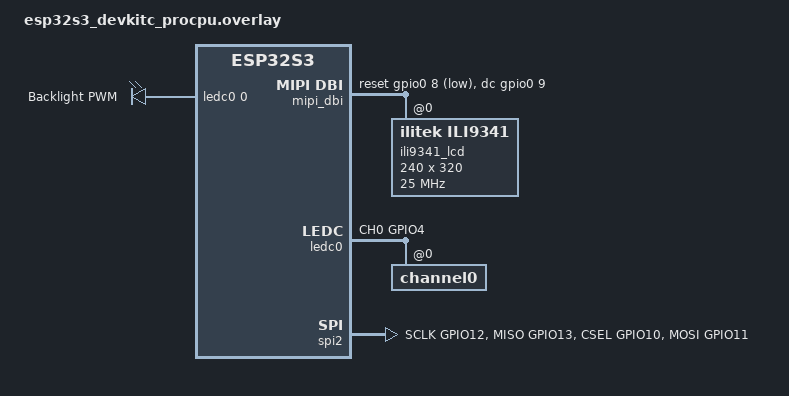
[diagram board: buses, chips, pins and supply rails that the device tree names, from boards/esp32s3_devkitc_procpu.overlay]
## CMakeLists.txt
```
cmake_minimum_required(VERSION 3.20.0)

set(CODECHECKER_ANALYZE_OPTS
    "--config;${CMAKE_SOURCE_DIR}/codechecker/codechecker.yml;"
    "--skip;${CMAKE_SOURCE_DIR}/codechecker/skip.codechecker"
    CACHE STRING "Code checker options")

# Find and load the Zephyr build system package
find_package(Zephyr REQUIRED HINTS $ENV{ZEPHYR_BASE})

# Define your project name
project(open_tempo)

# Target the application source code files
target_sources(app PRIVATE
    src/main.cpp
    src/GuiClock.cpp
    src/Threads.cpp
    
    src/Gui/GuiThread.cpp

    # Generated
    src/Gui/Generated/lv_font_roboto_mono_30.c
)
```

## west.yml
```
manifest:
  self:
    path: opentempo

  remotes:
    - name: zephyrproject-rtos
      url-base: https://github.com/zephyrproject-rtos

  projects:
    - name: zephyr
      remote: zephyrproject-rtos
      revision: main
      import:
        name-allowlist:
          - cmsis_6
          - hal_espressif
          - lvgl
          - hal_espressif
```

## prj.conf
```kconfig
CONFIG_CPP=y
CONFIG_STD_CPP23=y
CONFIG_CPP_EXCEPTIONS=y
CONFIG_REQUIRES_FULL_LIBCPP=y

CONFIG_MAIN_STACK_SIZE=8192

# --- Multi-core Support ---
CONFIG_SMP=n
CONFIG_MP_MAX_NUM_CPUS=2
CONFIG_DCACHE=n

# --- Display Framework ---
CONFIG_DISPLAY=y
CONFIG_ILI9341=y

# --- Modern Zephyr LVGL Core Initialization ---
CONFIG_LVGL=y
CONFIG_LV_USE_ILI9341=y
CONFIG_LV_COLOR_DEPTH_16=y
CONFIG_LV_Z_VDB_SIZE=20
CONFIG_LV_Z_MEM_POOL_SIZE=32768
CONFIG_LV_FONT_MONTSERRAT_24=y
CONFIG_LV_Z_DOUBLE_VDB=y
CONFIG_LV_USE_LOG=y
# CONFIG_LV_COLOR_16_SWAP=y

# --- Hardware System Specs ---
CONFIG_LOG=y
CONFIG_DMA=y
CONFIG_SPI=y
CONFIG_PWM=y
```

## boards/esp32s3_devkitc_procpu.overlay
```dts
#include <zephyr/dt-bindings/pinctrl/esp32s3-pinctrl.h>
#include <zephyr/dt-bindings/mipi_dbi/mipi_dbi.h>
#include <zephyr/dt-bindings/pwm/pwm.h>

/ {
    chosen {
        // Tells Zephyr's display sub-system (and graphics engines like LVGL) to target this screen
        zephyr,display = &ili9341_lcd;
    };

    aliases {
        backlight-pwm = &backlight_pwm_pin;
    };

    // Virtual MIPI-DBI bus required by modern Zephyr display drivers
    mipi_dbi {
        compatible = "zephyr,mipi-dbi-spi";
        spi-dev = <&spi2>;
        write-only;
        #address-cells = <1>;
        #size-cells = <0>;

        // Hardware control pins managed directly by the MIPI-DBI wrapper
        dc-gpios = <&gpio0 9 GPIO_ACTIVE_HIGH>;    /* D/C (Data/Command) Pin */
        reset-gpios = <&gpio0 8 GPIO_ACTIVE_LOW>;  /* RST (Reset) Pin */

        ili9341_lcd: ili9341@0 {
            compatible = "ilitek,ili9341";
            mipi-max-frequency = <25000000>;
            reg = <0>;
            pixel-format = <1>;
            rotation = <90>;
            h-mirror;
            width = <240>;
            height = <320>;
            status = "okay";
        };
    };

    backlight_pwm: backlight_pwm {
        compatible = "pwm-leds";
        backlight_pwm_pin: pwm_led_0 {
            pwms = <&ledc0 0 50000 PWM_POLARITY_NORMAL>;
            label = "Backlight PWM";
        };
    };
};

&pinctrl {
    ledc0_default: ledc0_default {
        group1 {
            pinmux = <LEDC_CH0_GPIO4>;
            output-enable;
        };
    };
};

&ledc0 {
    pinctrl-0 = <&ledc0_default>;
    pinctrl-names = "default";
    status = "okay";
    #address-cells = <1>;
    #size-cells = <0>;

    /* Allocate hardware timer resources for channel 0 */
    channel0@0 {
        reg = <0x0>;
        timer = <0>;
    };
};

&dma {
    status = "okay";
};

&pinctrl {
    spi2_custom: spi2_custom {
        group1 {
            pinmux = <SPIM2_SCLK_GPIO12>,
                     <SPIM2_MISO_GPIO13>,
                     <SPIM2_CSEL_GPIO10>;
        };
        group2 {
            pinmux = <SPIM2_MOSI_GPIO11>;
            output-low;
        };
    };
};

&spi2 {
    status = "okay";
    pinctrl-0 = <&spi2_custom>;
    pinctrl-names = "default";
    dmas = <&dma 0>, <&dma 1>;
    dma-names = "tx", "rx";
};
```

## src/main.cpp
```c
#include <zephyr/kernel.h>
#include <zephyr/sys/printk.h>

int main(void)
{
    printk("Main system initialized on Core %d\n", arch_curr_cpu()->id);

    while (true)
    {
        k_msleep(1000);
    }
    return 0;
}
```

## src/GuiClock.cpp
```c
#include <cstdint>

#include "GuiClock.hpp"

namespace gui
{
    GuiClock::GuiClock()
    {
        k_timer_init(&clockTimer, Callback, nullptr);
        k_timer_user_data_set(&clockTimer, this);
        k_timer_start(&clockTimer, K_SECONDS(1), K_SECONDS(1));
    }

    void GuiClock::SyncTime(uint32_t hours, uint32_t minutes, uint32_t seconds)
    {
        this->hours = hours;
        this->minutes = minutes;
        this->seconds = seconds;
    }

    void GuiClock::Callback(k_timer *timer)
    {
        GuiClock *instance = static_cast<GuiClock *>(k_timer_user_data_get(timer));

        instance->seconds++;

        if (instance->seconds >= 60)
        {
            instance->seconds = 0;
            instance->minutes++;
        }

        if (instance->minutes >= 60)
        {
            instance->minutes = 0;
            instance->hours++;
        }

        if (instance->hours >= 24)
        {
            instance->hours = 0;
        }
    }
} // namespace gui
```

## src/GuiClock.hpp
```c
#pragma once

#include <format>
#include <zephyr/kernel.h>
namespace gui
{
    class GuiClock
    {
      public:
        GuiClock();

        void SyncTime(uint32_t hours, uint32_t minutes, uint32_t seconds);

        std::string GetFormatetTime() const
        {
            return std::format("{:02}:{:02}:{:02}", hours, minutes, seconds);
        }

      private:
        k_timer clockTimer;
        uint32_t seconds = 0;
        uint32_t minutes = 0;
        uint32_t hours = 0;

        static void Callback(k_timer *timer);
    };
} // namespace gui
```

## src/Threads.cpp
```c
#include <zephyr/kernel.h>

#include "Gui/GuiThread.hpp"

#define GUI_THREAD_STACK_SIZE 4096
#define CLOCK_THREAD_STACK_SIZE 4096

void GuiThreadEntry(void * /*unused*/, void * /*unused*/, void * /*unused*/)
{
    static gui::GuiThread guiThread;
    guiThread.GuiThreadEntry();
}

K_THREAD_DEFINE(GuiThread, GUI_THREAD_STACK_SIZE, GuiThreadEntry, NULL, NULL, NULL, 0, 0, 0);
```
